VERSION 5.7 ;
BUSBITCHARS "[]" ;
DIVIDERCHAR "/" ;

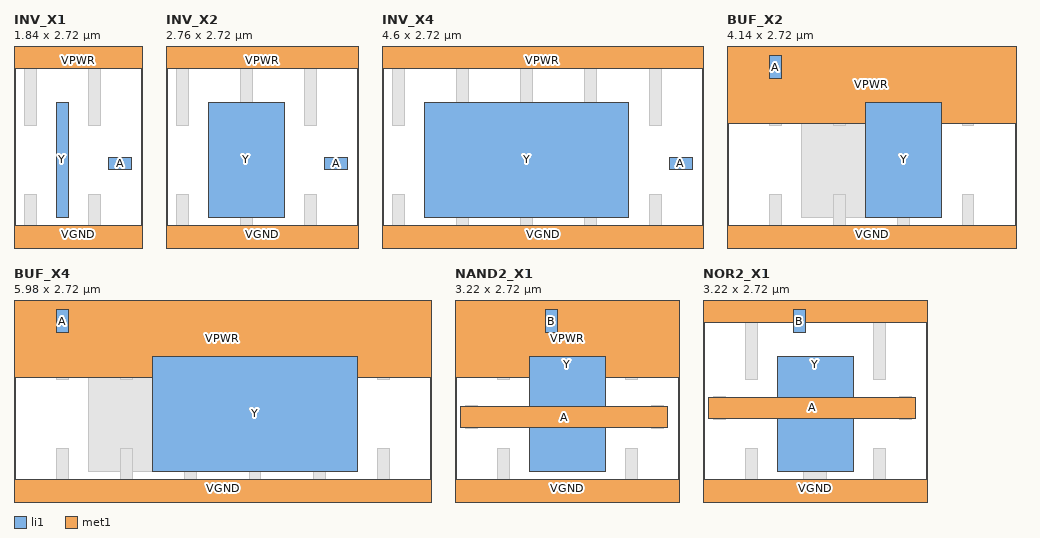
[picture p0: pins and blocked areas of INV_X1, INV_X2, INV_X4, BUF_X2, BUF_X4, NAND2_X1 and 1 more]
MACRO INV_X1
  CLASS CORE ;
  ORIGIN 0 0 ;
  SIZE 1.840 BY 2.720 ;
  SYMMETRY X Y ;
  SITE unithd ;
  PIN A
    DIRECTION INPUT ;
    USE SIGNAL ;
    PORT
      LAYER li1 ;
        RECT 1.355 1.045 1.685 1.215 ;
    END
  END A
  PIN Y
    DIRECTION OUTPUT ;
    USE SIGNAL ;
    PORT
      LAYER li1 ;
        RECT 0.605 0.355 0.775 2.000 ;
    END
  END Y
  PIN VPWR
    DIRECTION INOUT ;
    USE POWER ;
    SHAPE ABUTMENT ;
    PORT
      LAYER met1 ;
        RECT 0.000 2.480 1.840 2.960 ;
    END
  END VPWR
  PIN VGND
    DIRECTION INOUT ;
    USE GROUND ;
    SHAPE ABUTMENT ;
    PORT
      LAYER met1 ;
        RECT 0.000 -0.240 1.840 0.240 ;
    END
  END VGND
  OBS
    LAYER li1 ;
      RECT 0.145 1.670 0.315 2.720 ;
      RECT 1.065 1.670 1.235 2.720 ;
      RECT 0.145 0.000 0.315 0.685 ;
      RECT 1.065 0.000 1.235 0.685 ;
  END
END INV_X1

MACRO INV_X2
  CLASS CORE ;
  ORIGIN 0 0 ;
  SIZE 2.760 BY 2.720 ;
  SYMMETRY X Y ;
  SITE unithd ;
  PIN A
    DIRECTION INPUT ;
    USE SIGNAL ;
    PORT
      LAYER li1 ;
        RECT 2.275 1.045 2.605 1.215 ;
    END
  END A
  PIN Y
    DIRECTION OUTPUT ;
    USE SIGNAL ;
    PORT
      LAYER li1 ;
        RECT 0.605 0.355 1.695 2.000 ;
    END
  END Y
  PIN VPWR
    DIRECTION INOUT ;
    USE POWER ;
    SHAPE ABUTMENT ;
    PORT
      LAYER met1 ;
        RECT 0.000 2.480 2.760 2.960 ;
    END
  END VPWR
  PIN VGND
    DIRECTION INOUT ;
    USE GROUND ;
    SHAPE ABUTMENT ;
    PORT
      LAYER met1 ;
        RECT 0.000 -0.240 2.760 0.240 ;
    END
  END VGND
  OBS
    LAYER li1 ;
      RECT 0.145 1.670 0.315 2.720 ;
      RECT 1.065 1.670 1.235 2.720 ;
      RECT 1.985 1.670 2.155 2.720 ;
      RECT 0.145 0.000 0.315 0.685 ;
      RECT 1.065 0.000 1.235 0.685 ;
      RECT 1.985 0.000 2.155 0.685 ;
  END
END INV_X2

MACRO INV_X4
  CLASS CORE ;
  ORIGIN 0 0 ;
  SIZE 4.600 BY 2.720 ;
  SYMMETRY X Y ;
  SITE unithd ;
  PIN A
    DIRECTION INPUT ;
    USE SIGNAL ;
    PORT
      LAYER li1 ;
        RECT 4.115 1.045 4.445 1.215 ;
    END
  END A
  PIN Y
    DIRECTION OUTPUT ;
    USE SIGNAL ;
    PORT
      LAYER li1 ;
        RECT 0.605 0.355 3.535 2.000 ;
    END
  END Y
  PIN VPWR
    DIRECTION INOUT ;
    USE POWER ;
    SHAPE ABUTMENT ;
    PORT
      LAYER met1 ;
        RECT 0.000 2.480 4.600 2.960 ;
    END
  END VPWR
  PIN VGND
    DIRECTION INOUT ;
    USE GROUND ;
    SHAPE ABUTMENT ;
    PORT
      LAYER met1 ;
        RECT 0.000 -0.240 4.600 0.240 ;
    END
  END VGND
  OBS
    LAYER li1 ;
      RECT 0.145 1.670 0.315 2.720 ;
      RECT 1.065 1.670 1.235 2.720 ;
      RECT 1.985 1.670 2.155 2.720 ;
      RECT 2.905 1.670 3.075 2.720 ;
      RECT 3.825 1.670 3.995 2.720 ;
      RECT 0.145 0.000 0.315 0.685 ;
      RECT 1.065 0.000 1.235 0.685 ;
      RECT 1.985 0.000 2.155 0.685 ;
      RECT 2.905 0.000 3.075 0.685 ;
      RECT 3.825 0.000 3.995 0.685 ;
  END
END INV_X4

MACRO BUF_X2
  CLASS CORE ;
  ORIGIN 0 0 ;
  SIZE 4.140 BY 2.720 ;
  SYMMETRY X Y ;
  SITE unithd ;
  PIN A
    DIRECTION INPUT ;
    USE SIGNAL ;
    PORT
      LAYER li1 ;
        RECT 0.605 2.335 0.775 2.665 ;
    END
  END A
  PIN Y
    DIRECTION OUTPUT ;
    USE SIGNAL ;
    PORT
      LAYER li1 ;
        RECT 1.985 0.355 3.075 2.000 ;
    END
  END Y
  PIN VPWR
    DIRECTION INOUT ;
    USE POWER ;
    SHAPE ABUTMENT ;
    PORT
      LAYER met1 ;
        RECT 0.000 1.690 4.140 2.960 ;
    END
  END VPWR
  PIN VGND
    DIRECTION INOUT ;
    USE GROUND ;
    SHAPE ABUTMENT ;
    PORT
      LAYER met1 ;
        RECT 0.000 -0.240 4.140 0.240 ;
    END
  END VGND
  OBS
    LAYER li1 ;
      RECT 3.365 1.670 3.535 2.720 ;
      RECT 1.065 0.355 2.005 2.665 ;
      RECT 0.605 1.670 0.775 2.000 ;
      RECT 1.525 1.670 1.695 2.000 ;
      RECT 2.445 1.670 2.615 2.000 ;
      RECT 0.605 0.000 0.775 0.685 ;
      RECT 1.525 0.000 1.695 0.685 ;
      RECT 2.445 0.000 2.615 0.685 ;
      RECT 3.365 0.000 3.535 0.685 ;
  END
END BUF_X2

MACRO BUF_X4
  CLASS CORE ;
  ORIGIN 0 0 ;
  SIZE 5.980 BY 2.720 ;
  SYMMETRY X Y ;
  SITE unithd ;
  PIN A
    DIRECTION INPUT ;
    USE SIGNAL ;
    PORT
      LAYER li1 ;
        RECT 0.605 2.335 0.775 2.665 ;
    END
  END A
  PIN Y
    DIRECTION OUTPUT ;
    USE SIGNAL ;
    PORT
      LAYER li1 ;
        RECT 1.985 0.355 4.915 2.000 ;
    END
  END Y
  PIN VPWR
    DIRECTION INOUT ;
    USE POWER ;
    SHAPE ABUTMENT ;
    PORT
      LAYER met1 ;
        RECT 0.000 1.690 5.980 2.960 ;
    END
  END VPWR
  PIN VGND
    DIRECTION INOUT ;
    USE GROUND ;
    SHAPE ABUTMENT ;
    PORT
      LAYER met1 ;
        RECT 0.000 -0.240 5.980 0.240 ;
    END
  END VGND
  OBS
    LAYER li1 ;
      RECT 5.205 1.670 5.375 2.720 ;
      RECT 1.065 0.355 2.005 2.665 ;
      RECT 0.605 1.670 0.775 2.000 ;
      RECT 1.525 1.670 1.695 2.000 ;
      RECT 2.445 1.670 2.615 2.000 ;
      RECT 3.365 1.670 3.535 2.000 ;
      RECT 4.285 1.670 4.455 2.000 ;
      RECT 0.605 0.000 0.775 0.685 ;
      RECT 1.525 0.000 1.695 0.685 ;
      RECT 2.445 0.000 2.615 0.685 ;
      RECT 3.365 0.000 3.535 0.685 ;
      RECT 4.285 0.000 4.455 0.685 ;
      RECT 5.205 0.000 5.375 0.685 ;
  END
END BUF_X4

MACRO NAND2_X1
  CLASS CORE ;
  ORIGIN 0 0 ;
  SIZE 3.220 BY 2.720 ;
  SYMMETRY X Y ;
  SITE unithd ;
  PIN A
    DIRECTION INPUT ;
    USE SIGNAL ;
    PORT
      LAYER met1 ;
        RECT 0.085 0.985 3.045 1.275 ;
    END
  END A
  PIN B
    DIRECTION INPUT ;
    USE SIGNAL ;
    PORT
      LAYER li1 ;
        RECT 1.295 2.335 1.465 2.665 ;
    END
  END B
  PIN Y
    DIRECTION OUTPUT ;
    USE SIGNAL ;
    PORT
      LAYER li1 ;
        RECT 1.065 0.355 2.155 2.000 ;
    END
  END Y
  PIN VPWR
    DIRECTION INOUT ;
    USE POWER ;
    SHAPE ABUTMENT ;
    PORT
      LAYER met1 ;
        RECT 0.000 1.690 3.220 2.960 ;
    END
  END VPWR
  PIN VGND
    DIRECTION INOUT ;
    USE GROUND ;
    SHAPE ABUTMENT ;
    PORT
      LAYER met1 ;
        RECT 0.000 -0.240 3.220 0.240 ;
    END
  END VGND
  OBS
    LAYER li1 ;
      RECT 0.605 1.670 0.775 2.720 ;
      RECT 2.445 1.670 2.615 2.720 ;
      RECT 1.525 1.670 1.695 2.000 ;
      RECT 0.145 1.275 0.315 1.295 ;
      RECT 2.815 1.275 2.985 1.295 ;
      RECT 0.145 0.965 0.315 0.985 ;
      RECT 2.815 0.965 2.985 0.985 ;
      RECT 0.605 0.000 0.775 0.685 ;
      RECT 2.445 0.000 2.615 0.685 ;
  END
END NAND2_X1

MACRO NOR2_X1
  CLASS CORE ;
  ORIGIN 0 0 ;
  SIZE 3.220 BY 2.720 ;
  SYMMETRY X Y ;
  SITE unithd ;
  PIN A
    DIRECTION INPUT ;
    USE SIGNAL ;
    PORT
      LAYER met1 ;
        RECT 0.085 1.115 3.045 1.405 ;
    END
  END A
  PIN B
    DIRECTION INPUT ;
    USE SIGNAL ;
    PORT
      LAYER li1 ;
        RECT 1.295 2.335 1.465 2.665 ;
    END
  END B
  PIN Y
    DIRECTION OUTPUT ;
    USE SIGNAL ;
    PORT
      LAYER li1 ;
        RECT 1.065 0.355 2.155 2.000 ;
    END
  END Y
  PIN VPWR
    DIRECTION INOUT ;
    USE POWER ;
    SHAPE ABUTMENT ;
    PORT
      LAYER met1 ;
        RECT 0.000 2.480 3.220 2.960 ;
    END
  END VPWR
  PIN VGND
    DIRECTION INOUT ;
    USE GROUND ;
    SHAPE ABUTMENT ;
    PORT
      LAYER met1 ;
        RECT 0.000 -0.240 3.220 0.240 ;
    END
  END VGND
  OBS
    LAYER li1 ;
      RECT 0.605 1.670 0.775 2.720 ;
      RECT 2.445 1.670 2.615 2.720 ;
      RECT 0.145 1.405 0.315 1.425 ;
      RECT 2.815 1.405 2.985 1.425 ;
      RECT 0.145 1.095 0.315 1.115 ;
      RECT 2.815 1.095 2.985 1.115 ;
      RECT 0.605 0.000 0.775 0.685 ;
      RECT 2.445 0.000 2.615 0.685 ;
      RECT 1.445 0.000 1.775 0.605 ;
  END
END NOR2_X1

END LIBRARY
